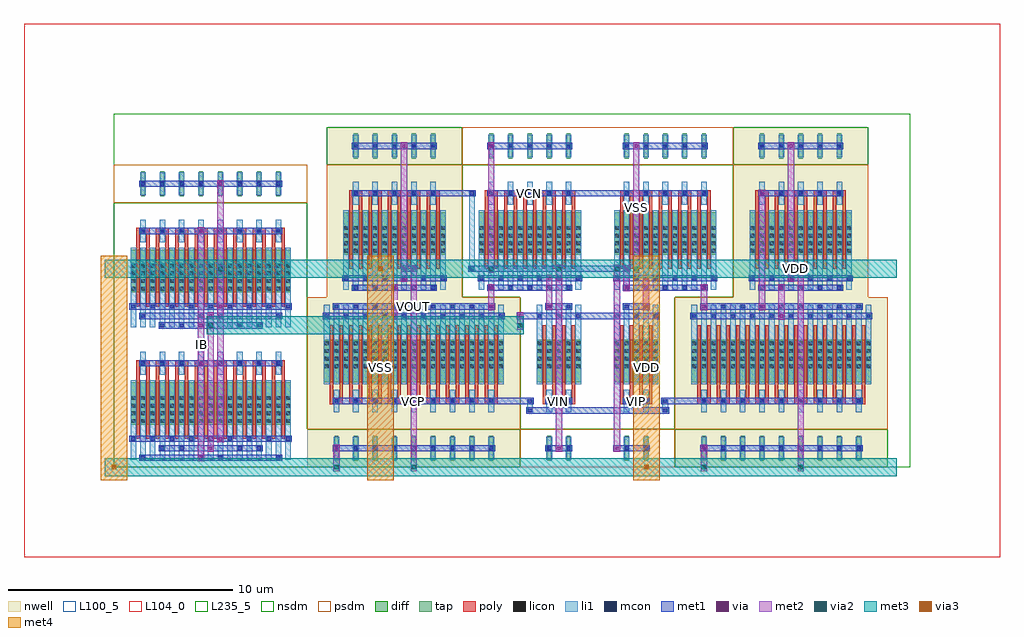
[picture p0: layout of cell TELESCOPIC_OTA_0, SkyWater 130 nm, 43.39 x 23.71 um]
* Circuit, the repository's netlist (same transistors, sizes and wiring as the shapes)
* NGSPICE file created from TELESCOPIC_OTA_0.ext - technology: sky130A

.subckt SCM_NMOS_21822889_X4_Y2_1774869491 a_230_1554# a_200_252# a_147_378#
X0 a_230_1554# a_200_252# a_147_378# a_147_378# sky130_fd_pr__nfet_01v8 ad=0.2646 pd=2.17 as=0.2646 ps=2.17 w=1.89 l=0.15 M=16
X1 a_147_378# a_200_252# a_200_252# a_147_378# sky130_fd_pr__nfet_01v8 ad=0.50085 pd=4.31 as=0.2646 ps=2.17 w=1.89 l=0.15 M=16
.ends

.subckt PMOS_4T_59417588_X9_Y1_1774869489 a_200_252# a_230_378# w_0_0# a_147_378#
X0 a_230_378# a_200_252# a_147_378# w_0_0# sky130_fd_pr__pfet_01v8 ad=0.2646 pd=2.17 as=0.2646 ps=2.17 w=1.89 l=0.15 M=18
.ends

.subckt NMOS_4T_74585927_X2_Y1_1774869487 a_200_252# a_230_378# a_147_378# a_241_1232#
X0 a_230_378# a_200_252# a_147_378# a_241_1232# sky130_fd_pr__nfet_01v8 ad=0.2646 pd=2.17 as=0.2646 ps=2.17 w=1.89 l=0.15 M=4
.ends

.subckt NMOS_4T_96640015_X5_Y1_1774869488 a_200_252# a_230_378# a_147_378# a_241_1232#
X0 a_230_378# a_200_252# a_147_378# a_241_1232# sky130_fd_pr__nfet_01v8 ad=0.2646 pd=2.17 as=0.2646 ps=2.17 w=1.89 l=0.15 M=10
.ends

.subckt PMOS_S_72158034_X5_Y1_1774869490 a_200_252# a_230_378# w_0_0#
X0 a_230_378# a_200_252# w_0_0# w_0_0# sky130_fd_pr__pfet_01v8 ad=0.2646 pd=2.17 as=0.2646 ps=2.17 w=1.89 l=0.15 M=10
.ends

.subckt TELESCOPIC_OTA_0 IB VCN VOUT VIP VIN VCP VSS VDD
XSCM_NMOS_21822889_X4_Y2_1774869491_0 m1_4128_1316# IB VSS SCM_NMOS_21822889_X4_Y2_1774869491
XPMOS_4T_59417588_X9_Y1_1774869489_0 VCP VOUT VDD m1_2462_1316# PMOS_4T_59417588_X9_Y1_1774869489
XNMOS_4T_74585927_X2_Y1_1774869487_0 VIN m1_3838_1400# m1_4128_1316# VSS NMOS_4T_74585927_X2_Y1_1774869487
XPMOS_4T_59417588_X9_Y1_1774869489_1 VCP m1_5730_1400# VDD m1_5902_1316# PMOS_4T_59417588_X9_Y1_1774869489
XNMOS_4T_74585927_X2_Y1_1774869487_1 VIP m1_4698_1400# m1_4128_1316# VSS NMOS_4T_74585927_X2_Y1_1774869487
XNMOS_4T_96640015_X5_Y1_1774869488_0 VCN VOUT m1_3838_1400# VSS NMOS_4T_96640015_X5_Y1_1774869488
XNMOS_4T_96640015_X5_Y1_1774869488_1 VCN m1_5730_1400# m1_4698_1400# VSS NMOS_4T_96640015_X5_Y1_1774869488
XPMOS_S_72158034_X5_Y1_1774869490_1 m1_5730_1400# m1_5902_1316# VDD PMOS_S_72158034_X5_Y1_1774869490
XPMOS_S_72158034_X5_Y1_1774869490_0 m1_5730_1400# m1_2462_1316# VDD PMOS_S_72158034_X5_Y1_1774869490
.ends

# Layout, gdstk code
from math import pi, radians
import gdstk
lib = gdstk.Library(unit=1e-6, precision=1e-09)
def R(c, l, rs):  # rectangles x0, y0, x1, y1
    for r in rs: c.add(gdstk.rectangle(r[:2], r[2:], *l))
def A(c, l, x, y, w, h, nx, ny, dx, dy):  # array of equal rectangles
    R(c, l, [(x+i*dx, y+j*dy, x+i*dx+w, y+j*dy+h) for i in range(nx) for j in range(ny)])
def P(c, l, *ps):  # polygons
    for p in ps: c.add(gdstk.Polygon(p, *l))
nwell = (64, 20)
diff = (65, 20)
tap = (65, 44)
poly = (66, 20)
licon = (66, 44)
li1 = (67, 20)
mcon = (67, 44)
met1 = (68, 20)
via = (68, 44)
met2 = (69, 20)
via2 = (69, 44)
met3 = (70, 20)
via3 = (70, 44)
met4 = (71, 20)
nsdm = (93, 44)
psdm = (94, 20)
L100_5 = (100, 5)
L104_0 = (104, 0)
L235_5 = (235, 5)

scm_nmos_21822889_x4_y2_ = lib.new_cell('SCM_NMOS_21822889_X4_Y2_1774869491')
R(scm_nmos_21822889_x4_y2_, diff, [(0.735,1.89,7.865,3.78), (0.735,7.77,7.865,9.66)])
A(scm_nmos_21822889_x4_y2_, tap, 1.205, 12.04, 0.17, 1.12, 8, 1, 0.86, 0)
A(scm_nmos_21822889_x4_y2_, poly, 1, 1.26, 0.15, 3.36, 16, 2, 0.43, 5.88)
A(scm_nmos_21822889_x4_y2_, poly, 1, 4.485, 0.58, 0.27, 8, 2, 0.86, 5.88)
A(scm_nmos_21822889_x4_y2_, licon, 0.775, 1.97, 0.17, 0.17, 3, 4, 0.43, 0.34)
A(scm_nmos_21822889_x4_y2_, licon, 1.635, 1.97, 0.17, 0.17, 3, 4, 0.43, 0.34)
A(scm_nmos_21822889_x4_y2_, licon, 2.495, 1.97, 0.17, 0.17, 3, 4, 0.43, 0.34)
A(scm_nmos_21822889_x4_y2_, licon, 3.355, 1.97, 0.17, 0.17, 3, 4, 0.43, 0.34)
A(scm_nmos_21822889_x4_y2_, licon, 4.215, 1.97, 0.17, 0.17, 3, 4, 0.43, 0.34)
A(scm_nmos_21822889_x4_y2_, licon, 5.075, 1.97, 0.17, 0.17, 3, 4, 0.43, 0.34)
A(scm_nmos_21822889_x4_y2_, licon, 5.935, 1.97, 0.17, 0.17, 3, 4, 0.43, 0.34)
A(scm_nmos_21822889_x4_y2_, licon, 6.795, 1.97, 0.17, 0.17, 3, 4, 0.43, 0.34)
A(scm_nmos_21822889_x4_y2_, licon, 1.205, 4.535, 0.17, 0.17, 8, 2, 0.86, 5.88)
A(scm_nmos_21822889_x4_y2_, licon, 0.775, 7.85, 0.17, 0.17, 3, 4, 0.43, 0.34)
A(scm_nmos_21822889_x4_y2_, licon, 1.635, 7.85, 0.17, 0.17, 3, 4, 0.43, 0.34)
A(scm_nmos_21822889_x4_y2_, licon, 2.495, 7.85, 0.17, 0.17, 3, 4, 0.43, 0.34)
A(scm_nmos_21822889_x4_y2_, licon, 3.355, 7.85, 0.17, 0.17, 3, 4, 0.43, 0.34)
A(scm_nmos_21822889_x4_y2_, licon, 4.215, 7.85, 0.17, 0.17, 3, 4, 0.43, 0.34)
A(scm_nmos_21822889_x4_y2_, licon, 5.075, 7.85, 0.17, 0.17, 3, 4, 0.43, 0.34)
A(scm_nmos_21822889_x4_y2_, licon, 5.935, 7.85, 0.17, 0.17, 3, 4, 0.43, 0.34)
A(scm_nmos_21822889_x4_y2_, licon, 6.795, 7.85, 0.17, 0.17, 3, 4, 0.43, 0.34)
R(scm_nmos_21822889_x4_y2_, licon, [(1.205,12.515,1.375,12.685), (1.205,12.515,1.375,12.685), (2.065,12.515,2.235,12.685), (2.065,12.515,2.235,12.685), (2.925,12.515,3.095,12.685), (2.925,12.515,3.095,12.685), (3.785,12.515,3.955,12.685), (3.785,12.515,3.955,12.685), (4.645,12.515,4.815,12.685), (4.645,12.515,4.815,12.685), (5.505,12.515,5.675,12.685), (5.505,12.515,5.675,12.685), (6.365,12.515,6.535,12.685), (6.365,12.515,6.535,12.685), (7.225,12.515,7.395,12.685), (7.225,12.515,7.395,12.685)])
A(scm_nmos_21822889_x4_y2_, li1, 0.735, 0.335, 0.25, 3.53, 17, 2, 0.43, 5.88)
A(scm_nmos_21822889_x4_y2_, li1, 1.165, 4.115, 0.25, 1.01, 8, 2, 0.86, 5.88)
A(scm_nmos_21822889_x4_y2_, li1, 1.165, 12.095, 0.25, 1.01, 8, 1, 0.86, 0)
A(scm_nmos_21822889_x4_y2_, mcon, 0.775, 1.175, 0.17, 0.17, 9, 2, 0.86, 5.88)
A(scm_nmos_21822889_x4_y2_, mcon, 1.205, 4.535, 0.17, 0.17, 8, 2, 0.86, 5.88)
A(scm_nmos_21822889_x4_y2_, mcon, 1.205, 12.515, 0.17, 0.17, 8, 1, 0.86, 0)
R(scm_nmos_21822889_x4_y2_, mcon, [(1.205,0.335,1.375,0.505), (3.785,0.335,3.955,0.505), (4.645,0.335,4.815,0.505), (7.225,0.335,7.395,0.505), (2.065,0.755,2.235,0.925), (2.925,0.755,3.095,0.925), (5.505,0.755,5.675,0.925), (6.365,0.755,6.535,0.925), (2.065,6.215,2.235,6.385), (2.925,6.215,3.095,6.385), (5.505,6.215,5.675,6.385), (6.365,6.215,6.535,6.385), (1.205,6.635,1.375,6.805), (3.785,6.635,3.955,6.805), (4.645,6.635,4.815,6.805), (7.225,6.635,7.395,6.805)])
R(scm_nmos_21822889_x4_y2_, met1, [(1.12,0.28,7.48,0.56), (1.98,0.7,6.62,0.98), (0.69,1.12,7.91,1.4), (1.12,4.48,7.48,4.76), (1.98,6.16,6.62,6.44), (1.12,6.58,7.48,6.86), (0.69,7,7.91,7.28), (1.12,10.36,7.48,10.64), (1.12,12.46,7.48,12.74)])
R(scm_nmos_21822889_x4_y2_, via, [(3.795,0.345,3.945,0.495), (4.225,0.765,4.375,0.915), (4.655,1.185,4.805,1.335), (3.795,4.545,3.945,4.695), (3.795,6.225,3.945,6.375), (4.225,6.645,4.375,6.795), (4.655,7.065,4.805,7.215), (3.795,10.425,3.945,10.575), (4.655,12.525,4.805,12.675)])
R(scm_nmos_21822889_x4_y2_, met2, [(3.73,0.26,4.01,10.66), (4.16,0.68,4.44,6.88), (4.59,1.1,4.87,12.76)])
R(scm_nmos_21822889_x4_y2_, nsdm, [(0,0,8.6,11.76)])
R(scm_nmos_21822889_x4_y2_, psdm, [(0,11.76,8.6,13.44)])
R(scm_nmos_21822889_x4_y2_, L100_5, [(0,0,8.6,13.44)])

pmos_s_72158034_x5_y1_17 = lib.new_cell('PMOS_S_72158034_X5_Y1_1774869490')
R(pmos_s_72158034_x5_y1_17, nwell, [(0,0,6.02,7.56)])
R(pmos_s_72158034_x5_y1_17, diff, [(0.735,1.89,5.285,3.78)])
A(pmos_s_72158034_x5_y1_17, tap, 1.205, 6.16, 0.17, 1.12, 5, 1, 0.86, 0)
A(pmos_s_72158034_x5_y1_17, poly, 1, 1.26, 0.15, 3.36, 10, 1, 0.43, 0)
A(pmos_s_72158034_x5_y1_17, poly, 1, 4.485, 0.58, 0.27, 5, 1, 0.86, 0)
A(pmos_s_72158034_x5_y1_17, licon, 0.775, 1.97, 0.17, 0.17, 3, 4, 0.43, 0.34)
A(pmos_s_72158034_x5_y1_17, licon, 1.635, 1.97, 0.17, 0.17, 3, 4, 0.43, 0.34)
A(pmos_s_72158034_x5_y1_17, licon, 2.495, 1.97, 0.17, 0.17, 3, 4, 0.43, 0.34)
A(pmos_s_72158034_x5_y1_17, licon, 3.355, 1.97, 0.17, 0.17, 3, 4, 0.43, 0.34)
A(pmos_s_72158034_x5_y1_17, licon, 4.215, 1.97, 0.17, 0.17, 3, 4, 0.43, 0.34)
A(pmos_s_72158034_x5_y1_17, licon, 1.205, 4.535, 0.17, 0.17, 5, 2, 0.86, 2.1)
A(pmos_s_72158034_x5_y1_17, li1, 0.735, 0.335, 0.25, 3.53, 11, 1, 0.43, 0)
A(pmos_s_72158034_x5_y1_17, li1, 1.165, 4.115, 0.25, 1.01, 5, 2, 0.86, 2.1)
A(pmos_s_72158034_x5_y1_17, mcon, 1.205, 0.335, 0.17, 0.17, 5, 2, 0.86, 4.2)
A(pmos_s_72158034_x5_y1_17, mcon, 0.775, 0.755, 0.17, 0.17, 6, 1, 0.86, 0)
A(pmos_s_72158034_x5_y1_17, mcon, 1.205, 6.635, 0.17, 0.17, 5, 1, 0.86, 0)
R(pmos_s_72158034_x5_y1_17, met1, [(1.12,0.28,4.9,0.56), (0.69,0.7,5.33,0.98), (1.12,4.48,4.9,4.76), (1.12,6.58,4.9,6.86)])
R(pmos_s_72158034_x5_y1_17, via, [(3.365,0.765,3.515,0.915), (3.365,6.645,3.515,6.795)])
R(pmos_s_72158034_x5_y1_17, met2, [(3.3,0.68,3.58,6.88)])
R(pmos_s_72158034_x5_y1_17, nsdm, [(0,5.88,6.02,7.56)])
R(pmos_s_72158034_x5_y1_17, psdm, [(0,0,6.02,5.88)])
R(pmos_s_72158034_x5_y1_17, L100_5, [(0,0,6.02,7.56)])

nmos_4t_96640015_x5_y1_1 = lib.new_cell('NMOS_4T_96640015_X5_Y1_1774869488')
R(nmos_4t_96640015_x5_y1_1, diff, [(0.735,1.89,5.285,3.78)])
A(nmos_4t_96640015_x5_y1_1, tap, 1.205, 6.16, 0.17, 1.12, 5, 1, 0.86, 0)
A(nmos_4t_96640015_x5_y1_1, poly, 1, 1.26, 0.15, 3.36, 10, 1, 0.43, 0)
A(nmos_4t_96640015_x5_y1_1, poly, 1, 4.485, 0.58, 0.27, 5, 1, 0.86, 0)
A(nmos_4t_96640015_x5_y1_1, licon, 0.775, 1.97, 0.17, 0.17, 3, 4, 0.43, 0.34)
A(nmos_4t_96640015_x5_y1_1, licon, 1.635, 1.97, 0.17, 0.17, 3, 4, 0.43, 0.34)
A(nmos_4t_96640015_x5_y1_1, licon, 2.495, 1.97, 0.17, 0.17, 3, 4, 0.43, 0.34)
A(nmos_4t_96640015_x5_y1_1, licon, 3.355, 1.97, 0.17, 0.17, 3, 4, 0.43, 0.34)
A(nmos_4t_96640015_x5_y1_1, licon, 4.215, 1.97, 0.17, 0.17, 3, 4, 0.43, 0.34)
A(nmos_4t_96640015_x5_y1_1, licon, 1.205, 4.535, 0.17, 0.17, 5, 2, 0.86, 2.1)
A(nmos_4t_96640015_x5_y1_1, li1, 0.735, 0.335, 0.25, 3.53, 11, 1, 0.43, 0)
A(nmos_4t_96640015_x5_y1_1, li1, 1.165, 4.115, 0.25, 1.01, 5, 2, 0.86, 2.1)
A(nmos_4t_96640015_x5_y1_1, mcon, 1.205, 0.335, 0.17, 0.17, 5, 2, 0.86, 4.2)
A(nmos_4t_96640015_x5_y1_1, mcon, 0.775, 0.755, 0.17, 0.17, 6, 1, 0.86, 0)
A(nmos_4t_96640015_x5_y1_1, mcon, 1.205, 6.635, 0.17, 0.17, 5, 1, 0.86, 0)
R(nmos_4t_96640015_x5_y1_1, met1, [(1.12,0.28,4.9,0.56), (0.69,0.7,5.33,0.98), (1.12,4.48,4.9,4.76), (1.12,6.58,4.9,6.86)])
R(nmos_4t_96640015_x5_y1_1, nsdm, [(0,0,6.02,5.88)])
R(nmos_4t_96640015_x5_y1_1, psdm, [(0,5.88,6.02,7.56)])
R(nmos_4t_96640015_x5_y1_1, L100_5, [(0,0,6.02,7.56)])

nmos_4t_74585927_x2_y1_1 = lib.new_cell('NMOS_4T_74585927_X2_Y1_1774869487')
R(nmos_4t_74585927_x2_y1_1, diff, [(0.735,1.89,2.705,3.78)])
R(nmos_4t_74585927_x2_y1_1, tap, [(1.205,6.16,1.375,7.28), (2.065,6.16,2.235,7.28)])
A(nmos_4t_74585927_x2_y1_1, poly, 1, 1.26, 0.15, 3.36, 4, 1, 0.43, 0)
R(nmos_4t_74585927_x2_y1_1, poly, [(1,4.485,1.58,4.755), (1.86,4.485,2.44,4.755)])
A(nmos_4t_74585927_x2_y1_1, licon, 0.775, 1.97, 0.17, 0.17, 3, 4, 0.43, 0.34)
A(nmos_4t_74585927_x2_y1_1, licon, 1.635, 1.97, 0.17, 0.17, 3, 4, 0.43, 0.34)
R(nmos_4t_74585927_x2_y1_1, licon, [(1.205,4.535,1.375,4.705), (2.065,4.535,2.235,4.705), (1.205,6.635,1.375,6.805), (2.065,6.635,2.235,6.805)])
A(nmos_4t_74585927_x2_y1_1, li1, 0.735, 0.335, 0.25, 3.53, 5, 1, 0.43, 0)
R(nmos_4t_74585927_x2_y1_1, li1, [(1.165,4.115,1.415,5.125), (2.025,4.115,2.275,5.125), (1.165,6.215,1.415,7.225), (2.025,6.215,2.275,7.225)])
A(nmos_4t_74585927_x2_y1_1, mcon, 0.775, 0.755, 0.17, 0.17, 3, 1, 0.86, 0)
R(nmos_4t_74585927_x2_y1_1, mcon, [(1.205,0.335,1.375,0.505), (2.065,0.335,2.235,0.505), (1.205,4.535,1.375,4.705), (2.065,4.535,2.235,4.705), (1.205,6.635,1.375,6.805), (2.065,6.635,2.235,6.805)])
R(nmos_4t_74585927_x2_y1_1, met1, [(1.12,0.28,2.32,0.56), (0.69,0.7,2.75,0.98), (1.12,4.48,2.32,4.76), (1.12,6.58,2.32,6.86)])
R(nmos_4t_74585927_x2_y1_1, nsdm, [(0,0,3.44,5.88)])
R(nmos_4t_74585927_x2_y1_1, psdm, [(0,5.88,3.44,7.56)])
R(nmos_4t_74585927_x2_y1_1, L100_5, [(0,0,3.44,7.56)])

pmos_4t_59417588_x9_y1_1 = lib.new_cell('PMOS_4T_59417588_X9_Y1_1774869489')
R(pmos_4t_59417588_x9_y1_1, nwell, [(0,0,9.46,7.56)])
R(pmos_4t_59417588_x9_y1_1, diff, [(0.735,1.89,8.725,3.78)])
A(pmos_4t_59417588_x9_y1_1, tap, 1.205, 6.16, 0.17, 1.12, 9, 1, 0.86, 0)
A(pmos_4t_59417588_x9_y1_1, poly, 1, 1.26, 0.15, 3.36, 18, 1, 0.43, 0)
A(pmos_4t_59417588_x9_y1_1, poly, 1, 4.485, 0.58, 0.27, 9, 1, 0.86, 0)
A(pmos_4t_59417588_x9_y1_1, licon, 0.775, 1.97, 0.17, 0.17, 3, 4, 0.43, 0.34)
A(pmos_4t_59417588_x9_y1_1, licon, 1.635, 1.97, 0.17, 0.17, 3, 4, 0.43, 0.34)
A(pmos_4t_59417588_x9_y1_1, licon, 2.495, 1.97, 0.17, 0.17, 3, 4, 0.43, 0.34)
A(pmos_4t_59417588_x9_y1_1, licon, 3.355, 1.97, 0.17, 0.17, 3, 4, 0.43, 0.34)
A(pmos_4t_59417588_x9_y1_1, licon, 4.215, 1.97, 0.17, 0.17, 3, 4, 0.43, 0.34)
A(pmos_4t_59417588_x9_y1_1, licon, 5.075, 1.97, 0.17, 0.17, 3, 4, 0.43, 0.34)
A(pmos_4t_59417588_x9_y1_1, licon, 5.935, 1.97, 0.17, 0.17, 3, 4, 0.43, 0.34)
A(pmos_4t_59417588_x9_y1_1, licon, 6.795, 1.97, 0.17, 0.17, 3, 4, 0.43, 0.34)
A(pmos_4t_59417588_x9_y1_1, licon, 7.655, 1.97, 0.17, 0.17, 3, 4, 0.43, 0.34)
A(pmos_4t_59417588_x9_y1_1, licon, 1.205, 4.535, 0.17, 0.17, 9, 2, 0.86, 2.1)
A(pmos_4t_59417588_x9_y1_1, li1, 0.735, 0.335, 0.25, 3.53, 19, 1, 0.43, 0)
A(pmos_4t_59417588_x9_y1_1, li1, 1.165, 4.115, 0.25, 1.01, 9, 2, 0.86, 2.1)
A(pmos_4t_59417588_x9_y1_1, mcon, 1.205, 0.335, 0.17, 0.17, 9, 2, 0.86, 4.2)
A(pmos_4t_59417588_x9_y1_1, mcon, 0.775, 0.755, 0.17, 0.17, 10, 1, 0.86, 0)
A(pmos_4t_59417588_x9_y1_1, mcon, 1.205, 6.635, 0.17, 0.17, 9, 1, 0.86, 0)
R(pmos_4t_59417588_x9_y1_1, met1, [(1.12,0.28,8.34,0.56), (0.69,0.7,8.77,0.98), (1.12,4.48,8.34,4.76), (1.12,6.58,8.34,6.86)])
R(pmos_4t_59417588_x9_y1_1, nsdm, [(0,5.88,9.46,7.56)])
R(pmos_4t_59417588_x9_y1_1, psdm, [(0,0,9.46,5.88)])
R(pmos_4t_59417588_x9_y1_1, L100_5, [(0,0,9.46,7.56)])

telescopic_ota_0 = lib.new_cell('TELESCOPIC_OTA_0')
R(telescopic_ota_0, li1, [(18.365,2.435,18.615,2.605), (18.365,2.435,18.615,2.605), (24.385,2.435,24.635,2.605), (24.385,2.435,24.635,2.605), (18.365,2.52,18.615,2.94), (24.385,2.52,24.635,2.94), (18.365,2.855,18.615,3.025), (18.365,2.855,18.615,3.025), (24.385,2.855,24.635,3.025), (24.385,2.855,24.635,3.025), (15.785,8.735,16.035,8.905), (15.785,8.735,16.035,8.905), (15.785,8.735,16.035,8.905), (15.785,8.735,16.035,8.905), (15.785,8.735,16.035,8.905), (15.785,8.735,16.035,8.905), (15.785,8.82,16.035,12.18), (15.785,12.095,16.035,12.265), (15.785,12.095,16.035,12.265), (15.785,12.095,16.035,12.265), (15.785,12.095,16.035,12.265), (15.785,12.095,16.035,12.265), (15.785,12.095,16.035,12.265)])
R(telescopic_ota_0, mcon, [(18.405,2.435,18.575,2.605), (18.405,2.435,18.575,2.605), (24.425,2.435,24.595,2.605), (24.425,2.435,24.595,2.605), (18.405,2.855,18.575,3.025), (18.405,2.855,18.575,3.025), (24.425,2.855,24.595,3.025), (24.425,2.855,24.595,3.025), (15.825,8.735,15.995,8.905), (15.825,8.735,15.995,8.905), (15.825,8.735,15.995,8.905), (15.825,8.735,15.995,8.905), (15.825,8.735,15.995,8.905), (15.825,8.735,15.995,8.905), (15.825,12.095,15.995,12.265), (15.825,12.095,15.995,12.265), (15.825,12.095,15.995,12.265), (15.825,12.095,15.995,12.265), (15.825,12.095,15.995,12.265), (15.825,12.095,15.995,12.265)])
R(telescopic_ota_0, met1, [(9.73,0.7,10.05,0.98), (9.73,0.7,10.05,0.98), (19.62,0.7,19.94,0.98), (19.62,0.7,19.94,0.98), (22.2,0.7,22.52,0.98), (22.2,0.7,22.52,0.98), (22.2,0.7,22.52,0.98), (22.36,0.7,22.79,0.98), (26.07,0.7,26.39,0.98), (26.07,0.7,26.39,0.98), (26.07,0.7,26.39,0.98), (18.32,2.38,18.66,2.66), (18.32,2.38,18.66,2.66), (18.49,2.38,24.51,2.66), (24.34,2.38,24.68,2.66), (24.34,2.38,24.68,2.66), (16.77,2.8,18.49,3.08), (18.32,2.8,18.66,3.08), (18.32,2.8,18.66,3.08), (24.34,2.8,24.68,3.08), (24.34,2.8,24.68,3.08), (24.51,2.8,26.23,3.08), (12.31,6.58,12.63,6.86), (12.31,6.58,12.63,6.86), (17.9,6.58,18.22,6.86), (17.9,6.58,18.22,6.86), (17.9,6.58,18.22,6.86), (17.9,6.58,18.22,6.86), (18.06,6.58,18.92,6.86), (20.64,6.58,22.36,6.86), (29.51,6.58,29.83,6.86), (29.51,6.58,29.83,6.86), (16.61,7,16.93,7.28), (16.61,7,16.93,7.28), (19.19,7,19.51,7.28), (19.19,7,19.51,7.28), (23.49,7,23.81,7.28), (23.49,7,23.81,7.28), (26.07,7,26.39,7.28), (26.07,7,26.39,7.28), (26.07,7,26.39,7.28), (26.07,7,26.39,7.28), (28.65,7,28.97,7.28), (28.65,7,28.97,7.28), (12.31,7.84,12.63,8.12), (12.31,7.84,12.63,8.12), (16.61,7.84,16.93,8.12), (16.61,7.84,16.93,8.12), (22.63,7.84,22.95,8.12), (22.63,7.84,22.95,8.12), (22.63,7.84,22.95,8.12), (22.63,7.84,22.95,8.12), (22.63,7.84,22.95,8.12), (22.63,7.84,22.95,8.12), (26.07,7.84,26.39,8.12), (26.07,7.84,26.39,8.12), (26.07,7.84,26.39,8.12), (26.07,7.84,26.39,8.12), (29.51,7.84,29.83,8.12), (29.51,7.84,29.83,8.12), (19.19,8.26,19.51,8.54), (19.19,8.26,19.51,8.54), (23.49,8.26,23.81,8.54), (23.49,8.26,23.81,8.54), (12.74,8.68,13.06,8.96), (12.74,8.68,13.06,8.96), (12.74,8.68,13.06,8.96), (12.74,8.68,13.06,8.96), (12.9,8.68,13.33,8.96), (13.17,8.68,13.49,8.96), (13.17,8.68,13.49,8.96), (13.17,8.68,13.49,8.96), (13.17,8.68,13.49,8.96), (15.74,8.68,16.08,8.96), (15.74,8.68,16.08,8.96), (15.74,8.68,16.08,8.96), (15.74,8.68,16.08,8.96), (15.74,8.68,16.08,8.96), (15.74,8.68,16.08,8.96), (15.91,8.68,22.79,8.96), (22.63,8.68,22.95,8.96), (22.63,8.68,22.95,8.96), (22.63,8.68,22.95,8.96), (22.63,8.68,22.95,8.96), (22.63,8.68,22.95,8.96), (22.63,8.68,22.95,8.96), (29.94,8.68,30.26,8.96), (29.94,8.68,30.26,8.96), (29.94,8.68,30.26,8.96), (29.94,8.68,30.26,8.96), (29.94,8.68,30.26,8.96), (30.1,8.68,30.53,8.96), (30.37,8.68,30.69,8.96), (30.37,8.68,30.69,8.96), (30.37,8.68,30.69,8.96), (30.37,8.68,30.69,8.96), (30.37,8.68,30.69,8.96), (14.19,12.04,15.91,12.32), (15.74,12.04,16.08,12.32), (15.74,12.04,16.08,12.32), (15.74,12.04,16.08,12.32), (15.74,12.04,16.08,12.32), (15.74,12.04,16.08,12.32), (15.74,12.04,16.08,12.32), (20.21,12.04,22.79,12.32), (28.65,12.04,28.97,12.32), (28.65,12.04,28.97,12.32), (16.61,14.14,16.93,14.42), (16.61,14.14,16.93,14.42), (16.61,14.14,16.93,14.42), (16.61,14.14,16.93,14.42), (23.06,14.14,23.38,14.42), (23.06,14.14,23.38,14.42), (23.06,14.14,23.38,14.42), (23.06,14.14,23.38,14.42), (23.06,14.14,23.38,14.42)])
P(telescopic_ota_0, met1, [(0,0),(0,0),(0,0),(0,0)],
  [(0,0),(0,0),(0,0),(0,0)],
  [(0,0),(0,0),(0,0),(0,0)],
  [(0,0),(0,0),(0,0),(0,0)],
  [(0,0),(0,0),(0,0),(0,0)],
  [(0,0),(0,0),(0,0),(0,0)],
  [(0,0),(0,0),(0,0),(0,0)],
  [(0,0),(0,0),(0,0),(0,0)],
  [(0,0),(0,0),(0,0),(0,0)],
  [(0,0),(0,0),(0,0),(0,0)],
  [(0,0),(0,0),(0,0),(0,0)],
  [(0,0),(0,0),(0,0),(0,0)],
  [(0,0),(0,0),(0,0),(0,0)],
  [(0,0),(0,0),(0,0),(0,0)],
  [(0,0),(0,0),(0,0),(0,0)],
  [(0,0),(0,0),(0,0),(0,0)],
  [(0,0),(0,0),(0,0),(0,0)],
  [(0,0),(0,0),(0,0),(0,0)],
  [(0,0),(0,0),(0,0),(0,0)],
  [(0,0),(0,0),(0,0),(0,0)],
  [(0,0),(0,0),(0,0),(0,0)],
  [(0,0),(0,0),(0,0),(0,0)],
  [(0,0),(0,0),(0,0),(0,0)],
  [(0,0),(0,0),(0,0),(0,0)],
  [(0,0),(0,0),(0,0),(0,0)],
  [(0,0),(0,0),(0,0),(0,0)],
  [(0,0),(0,0),(0,0),(0,0)],
  [(0,0),(0,0),(0,0),(0,0)],
  [(0,0),(0,0),(0,0),(0,0)],
  [(0,0),(0,0),(0,0),(0,0)],
  [(0,0),(0,0),(0,0),(0,0)],
  [(0,0),(0,0),(0,0),(0,0)],
  [(0,0),(0,0),(0,0),(0,0)])
R(telescopic_ota_0, via, [(9.815,0.765,9.965,0.915), (9.815,0.765,9.965,0.915), (19.705,0.765,19.855,0.915), (19.705,0.765,19.855,0.915), (22.285,0.765,22.435,0.915), (22.285,0.765,22.435,0.915), (22.285,0.765,22.435,0.915), (26.155,0.765,26.305,0.915), (26.155,0.765,26.305,0.915), (26.155,0.765,26.305,0.915), (12.395,6.645,12.545,6.795), (12.395,6.645,12.545,6.795), (17.985,6.645,18.135,6.795), (17.985,6.645,18.135,6.795), (17.985,6.645,18.135,6.795), (17.985,6.645,18.135,6.795), (29.595,6.645,29.745,6.795), (29.595,6.645,29.745,6.795), (16.695,7.065,16.845,7.215), (16.695,7.065,16.845,7.215), (19.275,7.065,19.425,7.215), (19.275,7.065,19.425,7.215), (23.575,7.065,23.725,7.215), (23.575,7.065,23.725,7.215), (26.155,7.065,26.305,7.215), (26.155,7.065,26.305,7.215), (26.155,7.065,26.305,7.215), (26.155,7.065,26.305,7.215), (28.735,7.065,28.885,7.215), (28.735,7.065,28.885,7.215), (12.395,7.905,12.545,8.055), (12.395,7.905,12.545,8.055), (16.695,7.905,16.845,8.055), (16.695,7.905,16.845,8.055), (22.715,7.905,22.865,8.055), (22.715,7.905,22.865,8.055), (22.715,7.905,22.865,8.055), (22.715,7.905,22.865,8.055), (22.715,7.905,22.865,8.055), (22.715,7.905,22.865,8.055), (26.155,7.905,26.305,8.055), (26.155,7.905,26.305,8.055), (26.155,7.905,26.305,8.055), (26.155,7.905,26.305,8.055), (29.595,7.905,29.745,8.055), (29.595,7.905,29.745,8.055), (19.275,8.325,19.425,8.475), (19.275,8.325,19.425,8.475), (23.575,8.325,23.725,8.475), (23.575,8.325,23.725,8.475), (12.825,8.745,12.975,8.895), (12.825,8.745,12.975,8.895), (12.825,8.745,12.975,8.895), (12.825,8.745,12.975,8.895), (13.255,8.745,13.405,8.895), (13.255,8.745,13.405,8.895), (13.255,8.745,13.405,8.895), (13.255,8.745,13.405,8.895), (22.715,8.745,22.865,8.895), (22.715,8.745,22.865,8.895), (22.715,8.745,22.865,8.895), (22.715,8.745,22.865,8.895), (22.715,8.745,22.865,8.895), (22.715,8.745,22.865,8.895), (30.025,8.745,30.175,8.895), (30.025,8.745,30.175,8.895), (30.025,8.745,30.175,8.895), (30.025,8.745,30.175,8.895), (30.025,8.745,30.175,8.895), (30.455,8.745,30.605,8.895), (30.455,8.745,30.605,8.895), (30.455,8.745,30.605,8.895), (30.455,8.745,30.605,8.895), (30.455,8.745,30.605,8.895), (28.735,12.105,28.885,12.255), (28.735,12.105,28.885,12.255), (16.695,14.205,16.845,14.355), (16.695,14.205,16.845,14.355), (16.695,14.205,16.845,14.355), (16.695,14.205,16.845,14.355), (23.145,14.205,23.295,14.355), (23.145,14.205,23.295,14.355), (23.145,14.205,23.295,14.355), (23.145,14.205,23.295,14.355), (23.145,14.205,23.295,14.355)])
R(telescopic_ota_0, met2, [(9.75,-0.185,10.03,0.185), (9.75,-0.185,10.03,0.185), (13.19,-0.185,13.47,0.185), (13.19,-0.185,13.47,0.185), (13.19,-0.185,13.47,0.185), (13.19,-0.185,13.47,0.185), (26.09,-0.185,26.37,0.185), (26.09,-0.185,26.37,0.185), (26.09,-0.185,26.37,0.185), (30.39,-0.185,30.67,0.185), (30.39,-0.185,30.67,0.185), (30.39,-0.185,30.67,0.185), (30.39,-0.185,30.67,0.185), (30.39,-0.185,30.67,0.185), (9.75,0,10.03,0.84), (13.19,0,13.47,8.82), (26.09,0,26.37,0.84), (30.39,0,30.67,8.82), (9.75,0.68,10.03,1), (9.75,0.68,10.03,1), (19.64,0.68,19.92,1), (19.64,0.68,19.92,1), (22.22,0.68,22.5,1), (22.22,0.68,22.5,1), (22.22,0.68,22.5,1), (26.09,0.68,26.37,1), (26.09,0.68,26.37,1), (26.09,0.68,26.37,1), (19.64,0.84,19.92,8.82), (22.22,0.84,22.5,8.82), (4.16,6.115,4.44,6.485), (4.16,6.115,4.44,6.485), (4.16,6.115,4.44,6.485), (4.16,6.115,4.44,6.485), (17.92,6.115,18.2,6.485), (17.92,6.115,18.2,6.485), (17.92,6.115,18.2,6.485), (17.92,6.115,18.2,6.485), (17.92,6.3,18.2,6.72), (12.33,6.56,12.61,6.88), (12.33,6.56,12.61,6.88), (17.92,6.56,18.2,6.88), (17.92,6.56,18.2,6.88), (17.92,6.56,18.2,6.88), (17.92,6.56,18.2,6.88), (29.53,6.56,29.81,6.88), (29.53,6.56,29.81,6.88), (12.33,6.72,12.61,7.98), (29.53,6.72,29.81,7.98), (16.63,6.98,16.91,7.3), (16.63,6.98,16.91,7.3), (19.21,6.98,19.49,7.3), (19.21,6.98,19.49,7.3), (23.51,6.98,23.79,7.3), (23.51,6.98,23.79,7.3), (26.09,6.98,26.37,7.3), (26.09,6.98,26.37,7.3), (26.09,6.98,26.37,7.3), (26.09,6.98,26.37,7.3), (28.67,6.98,28.95,7.3), (28.67,6.98,28.95,7.3), (16.63,7.14,16.91,7.98), (19.21,7.14,19.49,8.4), (23.51,7.14,23.79,8.4), (26.09,7.14,26.37,7.98), (28.67,7.14,28.95,12.18), (12.33,7.82,12.61,8.14), (12.33,7.82,12.61,8.14), (16.63,7.82,16.91,8.14), (16.63,7.82,16.91,8.14), (22.65,7.82,22.93,8.14), (22.65,7.82,22.93,8.14), (22.65,7.82,22.93,8.14), (22.65,7.82,22.93,8.14), (22.65,7.82,22.93,8.14), (22.65,7.82,22.93,8.14), (26.09,7.82,26.37,8.14), (26.09,7.82,26.37,8.14), (26.09,7.82,26.37,8.14), (26.09,7.82,26.37,8.14), (29.53,7.82,29.81,8.14), (29.53,7.82,29.81,8.14), (22.65,7.98,22.93,8.82), (19.21,8.24,19.49,8.56), (19.21,8.24,19.49,8.56), (23.51,8.24,23.79,8.56), (23.51,8.24,23.79,8.56), (4.59,8.635,4.87,9.005), (4.59,8.635,4.87,9.005), (4.59,8.635,4.87,9.005), (4.59,8.635,4.87,9.005), (4.59,8.635,4.87,9.005), (4.59,8.635,4.87,9.005), (16.63,8.635,16.91,9.005), (16.63,8.635,16.91,9.005), (16.63,8.635,16.91,9.005), (16.63,8.635,16.91,9.005), (19.64,8.635,19.92,9.005), (19.64,8.635,19.92,9.005), (22.22,8.635,22.5,9.005), (22.22,8.635,22.5,9.005), (22.22,8.635,22.5,9.005), (23.08,8.635,23.36,9.005), (23.08,8.635,23.36,9.005), (23.08,8.635,23.36,9.005), (23.08,8.635,23.36,9.005), (23.08,8.635,23.36,9.005), (12.76,8.66,13.04,8.98), (12.76,8.66,13.04,8.98), (12.76,8.66,13.04,8.98), (12.76,8.66,13.04,8.98), (13.19,8.66,13.47,8.98), (13.19,8.66,13.47,8.98), (13.19,8.66,13.47,8.98), (13.19,8.66,13.47,8.98), (22.65,8.66,22.93,8.98), (22.65,8.66,22.93,8.98), (22.65,8.66,22.93,8.98), (22.65,8.66,22.93,8.98), (22.65,8.66,22.93,8.98), (22.65,8.66,22.93,8.98), (29.96,8.66,30.24,8.98), (29.96,8.66,30.24,8.98), (29.96,8.66,30.24,8.98), (29.96,8.66,30.24,8.98), (29.96,8.66,30.24,8.98), (30.39,8.66,30.67,8.98), (30.39,8.66,30.67,8.98), (30.39,8.66,30.67,8.98), (30.39,8.66,30.67,8.98), (30.39,8.66,30.67,8.98), (16.63,8.82,16.91,14.28), (23.08,8.82,23.36,14.28), (28.67,12.02,28.95,12.34), (28.67,12.02,28.95,12.34), (16.63,14.12,16.91,14.44), (16.63,14.12,16.91,14.44), (16.63,14.12,16.91,14.44), (16.63,14.12,16.91,14.44), (23.08,14.12,23.36,14.44), (23.08,14.12,23.36,14.44), (23.08,14.12,23.36,14.44), (23.08,14.12,23.36,14.44), (23.08,14.12,23.36,14.44)])
P(telescopic_ota_0, met2, [(0,0),(0,0),(0,0),(0,0)],
  [(0,0),(0,0),(0,0),(0,0)],
  [(0,0),(0,0),(0,0),(0,0)],
  [(0,0),(0,0),(0,0),(0,0)],
  [(0,0),(0,0),(0,0),(0,0)],
  [(0,0),(0,0),(0,0),(0,0)])
R(telescopic_ota_0, via2, [(9.79,-0.1,9.99,0.1), (9.79,-0.1,9.99,0.1), (13.23,-0.1,13.43,0.1), (13.23,-0.1,13.43,0.1), (13.23,-0.1,13.43,0.1), (13.23,-0.1,13.43,0.1), (26.13,-0.1,26.33,0.1), (26.13,-0.1,26.33,0.1), (26.13,-0.1,26.33,0.1), (30.43,-0.1,30.63,0.1), (30.43,-0.1,30.63,0.1), (30.43,-0.1,30.63,0.1), (30.43,-0.1,30.63,0.1), (30.43,-0.1,30.63,0.1), (4.2,6.2,4.4,6.4), (4.2,6.2,4.4,6.4), (4.2,6.2,4.4,6.4), (4.2,6.2,4.4,6.4), (17.96,6.2,18.16,6.4), (17.96,6.2,18.16,6.4), (17.96,6.2,18.16,6.4), (17.96,6.2,18.16,6.4), (4.63,8.72,4.83,8.92), (4.63,8.72,4.83,8.92), (4.63,8.72,4.83,8.92), (4.63,8.72,4.83,8.92), (4.63,8.72,4.83,8.92), (4.63,8.72,4.83,8.92), (16.67,8.72,16.87,8.92), (16.67,8.72,16.87,8.92), (16.67,8.72,16.87,8.92), (16.67,8.72,16.87,8.92), (19.68,8.72,19.88,8.92), (19.68,8.72,19.88,8.92), (22.26,8.72,22.46,8.92), (22.26,8.72,22.46,8.92), (22.26,8.72,22.46,8.92), (23.12,8.72,23.32,8.92), (23.12,8.72,23.32,8.92), (23.12,8.72,23.32,8.92), (23.12,8.72,23.32,8.92), (23.12,8.72,23.32,8.92)])
A(telescopic_ota_0, met3, -0.4, -0.4, 4.24, 0.8, 3, 2, 3.44, 8.82)
A(telescopic_ota_0, met3, 23.68, -0.4, 4.24, 0.8, 3, 2, 3.44, 8.82)
R(telescopic_ota_0, met3, [(-0.165,-0.4,0.165,0.4), (9.725,-0.4,10.055,0.4), (9.725,-0.4,10.055,0.4), (9.92,-0.4,12.24,0.4), (11.44,-0.4,14.16,0.4), (13.165,-0.4,13.495,0.4), (13.165,-0.4,13.495,0.4), (13.165,-0.4,13.495,0.4), (13.165,-0.4,13.495,0.4), (13.36,-0.4,17.6,0.4), (16.8,-0.4,21.04,0.4), (20.24,-0.4,24.08,0.4), (23.28,-0.4,24.48,0.4), (23.515,-0.4,23.845,0.4), (26.065,-0.4,26.395,0.4), (26.065,-0.4,26.395,0.4), (26.065,-0.4,26.395,0.4), (30.365,-0.4,30.695,0.4), (30.365,-0.4,30.695,0.4), (30.365,-0.4,30.695,0.4), (30.365,-0.4,30.695,0.4), (30.365,-0.4,30.695,0.4), (4.135,5.9,4.465,6.7), (4.135,5.9,4.465,6.7), (4.135,5.9,4.465,6.7), (4.135,5.9,4.465,6.7), (4.3,5.9,18.06,6.7), (17.895,5.9,18.225,6.7), (17.895,5.9,18.225,6.7), (17.895,5.9,18.225,6.7), (17.895,5.9,18.225,6.7), (4.565,8.42,4.895,9.22), (4.565,8.42,4.895,9.22), (4.565,8.42,4.895,9.22), (4.565,8.42,4.895,9.22), (4.565,8.42,4.895,9.22), (4.565,8.42,4.895,9.22), (9.92,8.42,12.24,9.22), (11.44,8.42,14.16,9.22), (11.675,8.42,12.005,9.22), (13.36,8.42,17.6,9.22), (16.605,8.42,16.935,9.22), (16.605,8.42,16.935,9.22), (16.605,8.42,16.935,9.22), (16.605,8.42,16.935,9.22), (16.8,8.42,21.04,9.22), (19.615,8.42,19.945,9.22), (19.615,8.42,19.945,9.22), (20.24,8.42,24.08,9.22), (22.195,8.42,22.525,9.22), (22.195,8.42,22.525,9.22), (22.195,8.42,22.525,9.22), (23.055,8.42,23.385,9.22), (23.055,8.42,23.385,9.22), (23.055,8.42,23.385,9.22), (23.055,8.42,23.385,9.22), (23.055,8.42,23.385,9.22), (23.28,8.42,24.48,9.22)])
R(telescopic_ota_0, via3, [(-0.1,-0.1,0.1,0.1), (23.58,-0.1,23.78,0.1), (11.74,8.72,11.94,8.92)])
A(telescopic_ota_0, met4, -0.59, -0.59, 1.18, 10, 3, 1, 11.84, 0)
R(telescopic_ota_0, met4, [(-0.59,-0.165,0.59,0.165), (23.09,-0.165,24.27,0.165), (11.25,8.655,12.43,8.985)])
R(telescopic_ota_0, L104_0, [(-4,-4,39.39,19.71)])
R(telescopic_ota_0, L235_5, [(0,0,35.39,15.71)])
telescopic_ota_0.add(gdstk.Reference(scm_nmos_21822889_x4_y2_, (0,0)))
telescopic_ota_0.add(gdstk.Reference(pmos_s_72158034_x5_y1_17, (33.54,7.56), rotation=pi, x_reflection=True))
telescopic_ota_0.add(gdstk.Reference(pmos_s_72158034_x5_y1_17, (9.46,7.56)))
telescopic_ota_0.add(gdstk.Reference(nmos_4t_96640015_x5_y1_1, (27.52,7.56), rotation=pi, x_reflection=True))
telescopic_ota_0.add(gdstk.Reference(nmos_4t_96640015_x5_y1_1, (15.48,7.56)))
telescopic_ota_0.add(gdstk.Reference(nmos_4t_74585927_x2_y1_1, (21.5,7.56), x_reflection=True))
telescopic_ota_0.add(gdstk.Reference(nmos_4t_74585927_x2_y1_1, (21.5,7.56), rotation=pi))
telescopic_ota_0.add(gdstk.Reference(pmos_4t_59417588_x9_y1_1, (34.4,7.56), rotation=pi))
telescopic_ota_0.add(gdstk.Reference(pmos_4t_59417588_x9_y1_1, (8.6,7.56), x_reflection=True))
telescopic_ota_0.add(gdstk.Label('IB', (3.87,5.46), layer=69, texttype=5))
telescopic_ota_0.add(gdstk.Label('VCN', (18.49,12.18), layer=68, texttype=5))
telescopic_ota_0.add(gdstk.Label('VOUT', (13.33,7.14), layer=68, texttype=5))
telescopic_ota_0.add(gdstk.Label('VIP', (23.22,2.94), layer=68, texttype=5))
telescopic_ota_0.add(gdstk.Label('VIN', (19.78,2.94), layer=68, texttype=5))
telescopic_ota_0.add(gdstk.Label('VCP', (13.33,2.94), layer=68, texttype=5))
telescopic_ota_0.add(gdstk.Label('VSS', (11.84,4.41), layer=71, texttype=5))
telescopic_ota_0.add(gdstk.Label('VSS', (11.84,4.41), layer=71, texttype=5))
telescopic_ota_0.add(gdstk.Label('VSS', (11.84,4.41), layer=71, texttype=5))
telescopic_ota_0.add(gdstk.Label('VSS', (23.22,11.55), layer=69, texttype=5))
telescopic_ota_0.add(gdstk.Label('VSS', (11.84,4.41), layer=71, texttype=5))
telescopic_ota_0.add(gdstk.Label('VSS', (11.84,4.41), layer=71, texttype=5))
telescopic_ota_0.add(gdstk.Label('VSS', (11.84,4.41), layer=71, texttype=5))
telescopic_ota_0.add(gdstk.Label('VSS', (11.84,4.41), layer=71, texttype=5))
telescopic_ota_0.add(gdstk.Label('VSS', (11.84,4.41), layer=71, texttype=5))
telescopic_ota_0.add(gdstk.Label('VSS', (11.84,4.41), layer=71, texttype=5))
telescopic_ota_0.add(gdstk.Label('VSS', (11.84,4.41), layer=71, texttype=5))
telescopic_ota_0.add(gdstk.Label('VSS', (11.84,4.41), layer=71, texttype=5))
telescopic_ota_0.add(gdstk.Label('VSS', (11.84,4.41), layer=71, texttype=5))
telescopic_ota_0.add(gdstk.Label('VSS', (11.84,4.41), layer=71, texttype=5))
telescopic_ota_0.add(gdstk.Label('VSS', (11.84,4.41), layer=71, texttype=5))
telescopic_ota_0.add(gdstk.Label('VDD', (23.68,4.41), layer=71, texttype=5))
telescopic_ota_0.add(gdstk.Label('VDD', (30.315,8.82), layer=68, texttype=5))
telescopic_ota_0.add(gdstk.Label('VDD', (23.68,4.41), layer=71, texttype=5))
telescopic_ota_0.add(gdstk.Label('VDD', (23.68,4.41), layer=71, texttype=5))
telescopic_ota_0.add(gdstk.Label('VDD', (23.68,4.41), layer=71, texttype=5))
telescopic_ota_0.add(gdstk.Label('VDD', (23.68,4.41), layer=71, texttype=5))
telescopic_ota_0.add(gdstk.Label('VDD', (23.68,4.41), layer=71, texttype=5))
telescopic_ota_0.add(gdstk.Label('VDD', (23.68,4.41), layer=71, texttype=5))
telescopic_ota_0.add(gdstk.Label('VDD', (23.68,4.41), layer=71, texttype=5))
telescopic_ota_0.add(gdstk.Label('VDD', (23.68,4.41), layer=71, texttype=5))
telescopic_ota_0.add(gdstk.Label('VDD', (23.68,4.41), layer=71, texttype=5))
telescopic_ota_0.add(gdstk.Label('VDD', (23.68,4.41), layer=71, texttype=5))
telescopic_ota_0.add(gdstk.Label('VDD', (23.68,4.41), layer=71, texttype=5))
telescopic_ota_0.add(gdstk.Label('VDD', (23.68,4.41), layer=71, texttype=5))
telescopic_ota_0.add(gdstk.Label('VDD', (23.68,4.41), layer=71, texttype=5))

lib.write_gds('TELESCOPIC_OTA_0.gds')
